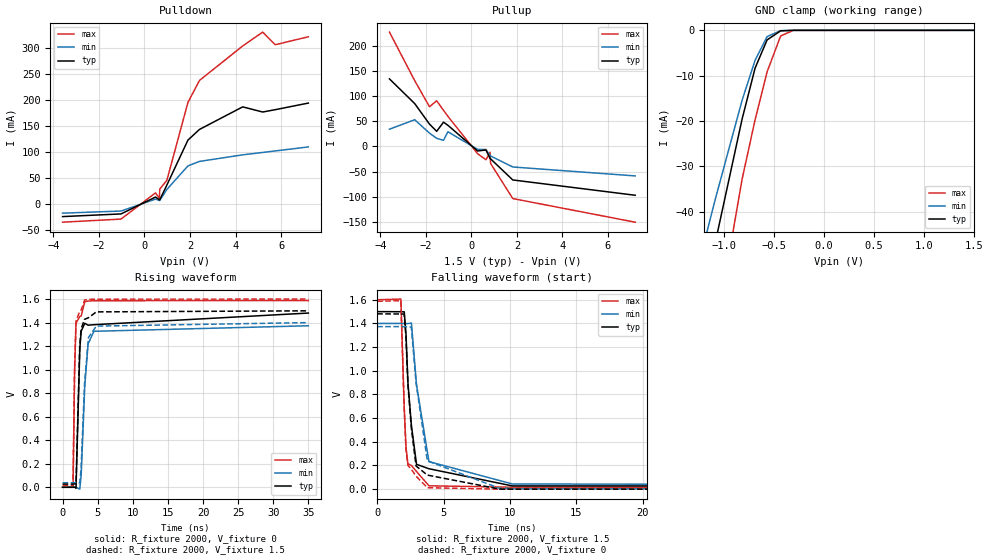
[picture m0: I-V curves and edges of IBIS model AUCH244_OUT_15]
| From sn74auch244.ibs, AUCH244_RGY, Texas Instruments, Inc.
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[Model]   AUCH244_OUT_15
Model_type  3-state
Enable   Active-Low
Vref =   0
Rref =   2000
Cref =   15p
Vmeas =   0.75
| variable   typ   min   max
C_comp   5.80pF   5.23pF   6.10pF
| C_pullup   5.20pF   0.65pF   12.77pF
| C_pulldown   6.55pF   5.62pF   10.14pF
| C_tri-state   5.80pF   5.23pF   6.10pF
[Temperature Range]   40   100   -40
| Ambient temperature   25   85   -40
[Voltage range]   1.5   1.4   1.6
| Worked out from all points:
|   slope of the pulldown table from 0 to 0.225 V, typ, clamps not added: 37.2 ohm
|   slope of the pullup table from 0 to 0.225 V, typ, clamps not added: 29.7 ohm
|   GND clamp passes 1 mA (typ) near -0.53 V on its own axis
|   rising waveform, R_fixture 2000, V_fixture 0: 20-80 % time 415ps typ, 649ps min, 258ps max; typ from 0 V to 1.48 V
|   falling waveform, R_fixture 2000, V_fixture 1.5: 20-80 % time 562ps typ, 892ps min, 311ps max; typ from 1.5 V to 0.027 V
|   rising waveform, R_fixture 2000, V_fixture 1.5: 20-80 % time 410ps typ, 643ps min, 254ps max; typ from 0.027 V to 1.5 V
|   falling waveform, R_fixture 2000, V_fixture 0: 20-80 % time 559ps typ, 887ps min, 309ps max; typ from 1.48 V to 0 V
[GND Clamp]
| AUCH244_OUT_15
|   Voltage   I(typ)   I(min)   I(max)
-3.6V     -322.8mA   -271.3mA   -392.8mA
-1.475V   -88.58mA   -71.53mA   -117.9mA
-1.34V    -73.9mA    -59.4mA    -100.2mA
-1.3V     -69.58mA   -55.84mA   -94.96mA
-1.135V   -51.89mA   -41.37mA   -73.3mA
-1.085V   -46.59mA   -37.07mA   -66.74mA
-820mV    -19.61mA   -15.46mA   -32.88mA
-690mV    -8.335mA   -6.603mA   -19.75mA
-570mV    -2.107mA   -1.377mA   -9.166mA
-435mV    -119.4uA   -67.95uA   -1.249mA
-310mV    -3.104uA   -3.773uA   -25uA
1.5V      550.3pA    10.34nA    544.8pA
[Pulldown]
| AUCH244_OUT_15
|   Voltage   I(typ)   I(min)   I(max)
-3.6V     -23.87mA   -17.26mA   -34.61mA
-1.03V    -18.71mA   -13.15mA   -28.63mA
485mV     13.68mA    9.737mA    21.72mA
660mV     8.179mA    6.953mA    10.96mA
670mV     8.319mA    7.1mA      28.79mA
985mV     36.88mA    28.41mA    46.12mA
1.91V     123.2mA    73.57mA    195.6mA
2.415V    143.6mA    82.17mA    237.7mA
4.315V    187mA      94.84mA    304mA
5.195V    177.1mA    99.4mA     330.7mA
5.745V    181.6mA    102.3mA    306.4mA
7.2V      194.3mA    110mA      321.7mA
[Pullup]
| AUCH244_OUT_15
|   Voltage   I(typ)   I(min)   I(max)
-3.6V     133.9mA    34.19mA    226.6mA
-2.49V    84.93mA    52.91mA    130.4mA
-1.84V    44.23mA    26.42mA    78.7mA
-1.525V   29.94mA    16.1mA     90.45mA
-1.225V   48.04mA    12.14mA    71.67mA
-1.03V    41.9mA     29.08mA    59.59mA
275mV     -9.031mA   -5.857mA   -14.38mA
640mV     -6.934mA   -6.165mA   -26.37mA
820mV     -23.65mA   -18mA      -11.49mA
845mV     -24.61mA   -18.86mA   -33.67mA
1.82V     -66.42mA   -40.7mA    -103.3mA
7.2V      -96.75mA   -58.41mA   -150.1mA
[Ramp]
| AUCH244_OUT_15
| variable   typ   min   max
dV/dt_r   0.90/4.22E-10   0.83/6.56E-10   0.96/2.59E-10
dV/dt_f   0.89/5.67E-10   0.82/8.95E-10   0.95/3.11E-10
R_load = 2000
[Rising Waveform]
| AUCH244_OUT_15
R_fixture =   2000
C_fixture =   0
L_fixture =   0
V_fixture =   0
V_fixture_min = 0
V_fixture_max = 0
|   Time   V(typ)   V(min)   V(max)
0s        9.799nV    37.56nV    981.3pV
1.495ns   8.668uV    -7.95uV    4.022mV
1.715ns   1.584mV    -21.38uV   990.6mV
1.915ns   -8.391mV   228.8uV    1.395V
2.455ns   1.179V     -15.98mV   1.453V
2.655ns   1.327V     108.2mV    1.457V
3.16ns    1.394V     858.1mV    1.577V
3.635ns   1.378V     1.218V     1.583V
4.46ns    1.382V     1.326V     1.586V
34.99ns   1.481V     1.373V     1.587V
[Falling Waveform]
| AUCH244_OUT_15
R_fixture =   2000
C_fixture =   0
L_fixture =   0
V_fixture =   1.5
V_fixture_min = 1.4
V_fixture_max = 1.6
|   Time   V(typ)   V(min)   V(max)
0s        1.5V       1.4V       1.6V
1.785ns   1.499V     1.4V       1.606V
2.04ns    1.498V     1.4V       686.1mV
2.175ns   1.302V     1.398V     348.3mV
2.32ns    896mV      1.399V     213.7mV
2.58ns    538.5mV    1.403V     199.7mV
2.965ns   209.8mV    881.4mV    149.2mV
3.9ns     172.5mV    232.9mV    28.58mV
10.18ns   27.54mV    43.93mV    16.5mV
34.99ns   27.21mV    38.76mV    16.42mV
[Rising Waveform]
| AUCH244_OUT_15
R_fixture =   2000
C_fixture =   0
L_fixture =   0
V_fixture =   1.5
V_fixture_min = 1.4
V_fixture_max = 1.6
|   Time   V(typ)   V(min)   V(max)
0s        27.17mV    38.75mV    16.4mV
1.485ns   27.18mV    38.74mV    17.04mV
1.72ns    28.78mV    38.73mV    1.033V
1.915ns   29.49mV    38.98mV    1.414V
2.445ns   1.201V     36.69mV    1.495V
2.64ns    1.346V     160.9mV    1.505V
3.13ns    1.428V     880.7mV    1.592V
3.685ns   1.441V     1.273V     1.597V
4.805ns   1.491V     1.37V      1.599V
34.99ns   1.5V       1.4V       1.6V
[Falling Waveform]
| AUCH244_OUT_15
R_fixture =   2000
C_fixture =   0
L_fixture =   0
V_fixture =   0
V_fixture_min = 0
V_fixture_max = 0
|   Time   V(typ)   V(min)   V(max)
0s        1.481V     1.373V     1.587V
1.785ns   1.48V      1.373V     1.592V
2.035ns   1.479V     1.372V     685.7mV
2.17ns    1.286V     1.371V     337.1mV
2.315ns   887.8mV    1.372V     200.6mV
2.575ns   515.4mV    1.369V     167.2mV
2.93ns    195.8mV    899.4mV    110mV
3.78ns    118.9mV    239.7mV    12.31mV
9.235ns   434.7uV    5.896mV    117.1uV
34.99ns   40.58uV    6.202uV    17.92uV
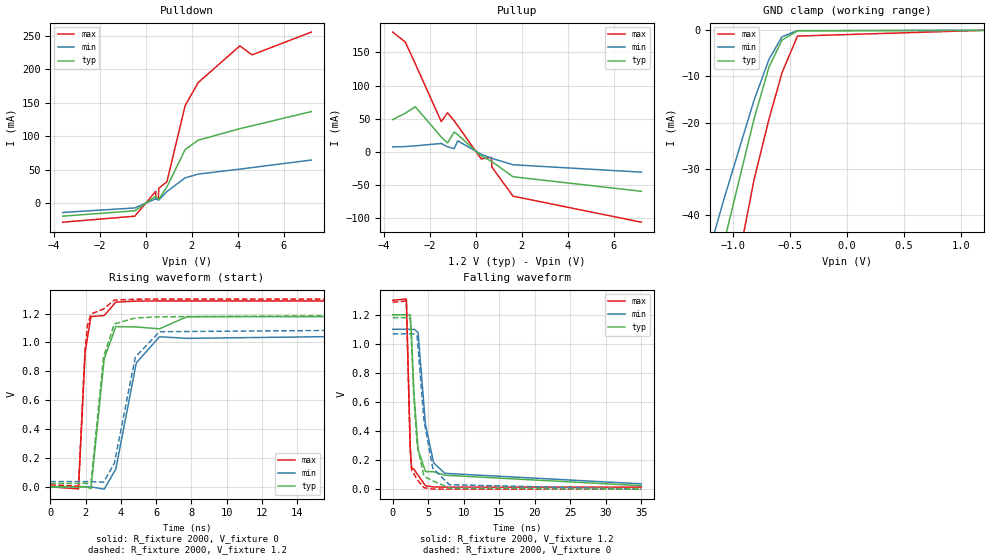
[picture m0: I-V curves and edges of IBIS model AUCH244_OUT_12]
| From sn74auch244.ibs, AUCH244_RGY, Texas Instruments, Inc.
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[Model]   AUCH244_OUT_12
Model_type  3-state
Enable   Active-Low
Vref =   0
Rref =   2000
Cref =   15p
Vmeas =   0.6
| variable   typ   min   max
C_comp   5.91pF   5.37pF   6.19pF
| C_pullup   5.14pF   0.31pF   10.09pF
| C_pulldown   6.52pF   5.74pF   7.72pF
| C_tri-state   5.91pF   5.37pF   6.19pF
[Temperature Range]   40   100   -40
| Ambient temperature   25   85   -40
[Voltage range]   1.2   1.1   1.3
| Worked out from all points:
|   slope of the pulldown table from 0 to 0.18 V, typ, clamps not added: 42.1 ohm
|   slope of the pullup table from 0 to 0.18 V, typ, clamps not added: 38.3 ohm
|   GND clamp passes 1 mA (typ) near -0.53 V on its own axis
|   rising waveform, R_fixture 2000, V_fixture 0: 20-80 % time 607ps typ, 1.03ns min, 332ps max; typ from 0 V to 1.18 V
|   falling waveform, R_fixture 2000, V_fixture 1.2: 20-80 % time 893ps typ, 1.4ns min, 432ps max; typ from 1.2 V to 0.024 V
|   rising waveform, R_fixture 2000, V_fixture 1.2: 20-80 % time 596ps typ, 1.03ns min, 326ps max; typ from 0.024 V to 1.2 V
|   falling waveform, R_fixture 2000, V_fixture 0: 20-80 % time 880ps typ, 1.33ns min, 425ps max; typ from 1.18 V to 0 V
[GND Clamp]
| AUCH244_OUT_12
|   Voltage   I(typ)   I(min)   I(max)
-3.6V     -322.8mA   -271.3mA   -392.8mA
-1.47V    -88.04mA   -71.07mA   -117.2mA
-1.425V   -83.13mA   -67.01mA   -111.4mA
-1.3V     -69.58mA   -55.84mA   -94.96mA
-1.26V    -65.26mA   -52.3mA    -89.71mA
-1.11V    -49.24mA   -39.21mA   -70.02mA
-1.075V   -45.54mA   -36.21mA   -65.43mA
-815mV    -19.13mA   -15.09mA   -32.31mA
-685mV    -7.974mA   -6.312mA   -19.28mA
-570mV    -2.107mA   -1.377mA   -9.166mA
-435mV    -119.4uA   -67.95uA   -1.249mA
1.2V      442.5pA    10.22nA    389.6pA
[Pulldown]
| AUCH244_OUT_12
|   Voltage   I(typ)   I(min)   I(max)
-3.6V     -19.18mA   -13.63mA   -28.17mA
-470mV    -11.13mA   -6.91mA    -19.23mA
440mV     10.48mA    6.706mA    17.92mA
445mV     10.59mA    6.769mA    6.318mA
560mV     5.857mA    4.698mA    8.209mA
570mV     5.97mA     4.786mA    22.41mA
925mV     24.38mA    17.54mA    32.09mA
1.72V     80.36mA    38.11mA    146mA
2.285V    94.25mA    43.63mA    180.3mA
4.095V    111.5mA    51.07mA    235.1mA
4.625V    115.8mA    53.41mA    221.7mA
7.2V      137mA      64.62mA    255.7mA
[Pullup]
| AUCH244_OUT_12
|   Voltage   I(typ)   I(min)   I(max)
-3.6V     48.8mA     7.73mA     180.5mA
-3.05V    58.5mA     8.2mA      165.4mA
-2.62V    68.11mA    9.305mA    132.9mA
-1.49V    22.6mA     12.87mA    45.69mA
-1.22V    13.65mA    7.955mA    59.11mA
-930mV    30.05mA    5.089mA    46.94mA
-775mV    26.1mA     16.83mA    39.5mA
245mV     -5.916mA   -3.381mA   -10.43mA
690mV     -14.05mA   -9.319mA   -7.997mA
705mV     -14.25mA   -9.473mA   -22.45mA
1.625V    -37.21mA   -19.16mA   -66.42mA
7.2V      -59.11mA   -30.28mA   -105.6mA
[Ramp]
| AUCH244_OUT_12
| variable   typ   min   max
dV/dt_r   0.72/6.09E-10   0.65/1.04E-09   0.78/3.37E-10
dV/dt_f   0.71/8.95E-10   0.64/1.40E-09   0.78/4.35E-10
R_load = 2000
[Rising Waveform]
| AUCH244_OUT_12
R_fixture =   2000
C_fixture =   0
L_fixture =   0
V_fixture =   0
V_fixture_min = 0
V_fixture_max = 0
|   Time   V(typ)   V(min)   V(max)
0s        9.189nV    39.93nV    791.2pV
1.6ns     -9.428uV   -3.122uV   -13.91mV
1.975ns   1.334mV    -22.29uV   931.3mV
2.305ns   -12.2mV    60.75uV    1.179V
3.055ns   886.6mV    -15.95mV   1.186V
3.715ns   1.109V     123.4mV    1.279V
4.875ns   1.107V     858.2mV    1.286V
6.19ns    1.094V     1.039V     1.287V
7.75ns    1.178V     1.028V     1.287V
34.99ns   1.18V      1.069V     1.287V
[Falling Waveform]
| AUCH244_OUT_12
R_fixture =   2000
C_fixture =   0
L_fixture =   0
V_fixture =   1.2
V_fixture_min = 1.1
V_fixture_max = 1.3
|   Time   V(typ)   V(min)   V(max)
0s        1.2V       1.1V       1.3V
1.92ns    1.2V       1.1V       1.308V
2.47ns    1.199V     1.1V       287.2mV
2.66ns    1.034V     1.098V     147.2mV
2.995ns   653.2mV    1.101V     136.9mV
3.575ns   269.8mV    1.078V     95.36mV
4.61ns    121.2mV    444.2mV    23.38mV
5.76ns    120mV      181.3mV    14.93mV
7.34ns    96.07mV    108.9mV    14.15mV
34.99ns   24.03mV    36.64mV    13.88mV
[Rising Waveform]
| AUCH244_OUT_12
R_fixture =   2000
C_fixture =   0
L_fixture =   0
V_fixture =   1.2
V_fixture_min = 1.1
V_fixture_max = 1.3
|   Time   V(typ)   V(min)   V(max)
0s        23.98mV    36.61mV    13.86mV
1.6ns     23.97mV    36.6mV     5.31mV
1.97ns    25.19mV    36.59mV    950.5mV
2.11ns    22.28mV    36.56mV    1.118V
2.305ns   26.37mV    36.68mV    1.197V
3.02ns    899.5mV    31.99mV    1.231V
3.63ns    1.128V     163.3mV    1.293V
4.82ns    1.169V     898.1mV    1.299V
6.185ns   1.177V     1.074V     1.3V
34.99ns   1.2V       1.1V       1.3V
[Falling Waveform]
| AUCH244_OUT_12
R_fixture =   2000
C_fixture =   0
L_fixture =   0
V_fixture =   0
V_fixture_min = 0
V_fixture_max = 0
|   Time   V(typ)   V(min)   V(max)
0s        1.18V      1.069V     1.287V
1.92ns    1.18V      1.069V     1.294V
2.46ns    1.176V     1.069V     275.6mV
2.65ns    1.013V     1.067V     134.2mV
2.965ns   640.6mV    1.069V     109.3mV
3.44ns    305.8mV    1.053V     65.29mV
4.4ns     88.28mV    473.4mV    9.989mV
5.64ns    57.55mV    144.3mV    929.8uV
7.97ns    7.606mV    30.8mV     202.3uV
34.99ns   50.29uV    16.34uV    18.98uV
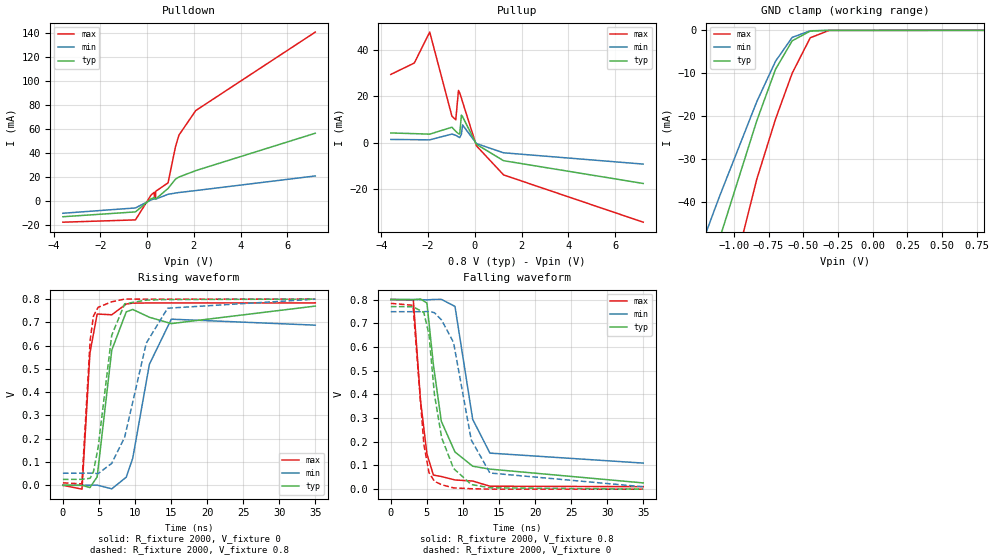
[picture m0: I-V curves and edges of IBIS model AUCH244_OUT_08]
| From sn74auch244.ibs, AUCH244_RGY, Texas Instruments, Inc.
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[Model]   AUCH244_OUT_08
Model_type  3-state
Enable   Active-Low
Vref =   0
Rref =   2000
Cref =   15p
Vmeas =   0.4
| variable   typ   min   max
C_comp   6.01pF   5.50pF   6.26pF
| C_pullup   6.18pF   1.68pF   8.54pF
| C_pulldown   6.67pF   6.06pF   7.13pF
| C_tri-state   6.01pF   5.50pF   6.26pF
[Temperature Range]   40   100   -40
| Ambient temperature   25   85   -40
[Voltage range]   0.8   0.8   0.8
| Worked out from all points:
|   slope of the pulldown table from 0 to 0.12 V, typ, clamps not added: 77.5 ohm
|   slope of the pullup table from 0 to 0.12 V, typ, clamps not added: 92.9 ohm
|   GND clamp passes 1 mA (typ) near -0.53 V on its own axis
|   rising waveform, R_fixture 2000, V_fixture 0: 20-80 % time 1.8ns typ, 2.48ns min, 963ps max; typ from 0 V to 0.77 V
|   falling waveform, R_fixture 2000, V_fixture 0.8: 20-80 % time 2.75ns typ, 2.16ns min, 1.41ns max; typ from 0.8 V to 0.026 V
|   rising waveform, R_fixture 2000, V_fixture 0.8: 20-80 % time 1.83ns typ, 3.55ns min, 910ps max; typ from 0.025 V to 0.8 V
|   falling waveform, R_fixture 2000, V_fixture 0: 20-80 % time 2.26ns typ, 2.82ns min, 1.27ns max; typ from 0.77 V to 0 V
[GND Clamp]
| AUCH244_OUT_08
|   Voltage   I(typ)   I(min)   I(max)
-3.6V     -322.8mA   -271.3mA   -392.8mA
-1.495V   -90.76mA   -73.33mA   -120.5mA
-1.455V   -86.4mA    -69.72mA   -115.3mA
-1.31V    -70.66mA   -56.73mA   -96.27mA
-1.14V    -52.42mA   -41.8mA    -73.96mA
-1.1V     -48.18mA   -38.36mA   -68.71mA
-835mV    -21.05mA   -16.6mA    -34.66mA
-700mV    -9.079mA   -7.199mA   -20.67mA
-580mV    -2.442mA   -1.648mA   -9.983mA
-450mV    -176.5uA   -96.05uA   -1.735mA
-315mV    -3.617uA   -4.294uA   -30.24uA
800mV     320.2pA    582.3pA    244.4pA
[Pulldown]
| AUCH244_OUT_08
|   Voltage   I(typ)   I(min)   I(max)
-3.6V     -12.84mA   -9.953mA   -17.38mA
-495mV    -8.803mA   -5.523mA   -15.47mA
175mV     2.059mA    1.185mA    5.31mA
310mV     3.174mA    2.053mA    7.502mA
315mV     3.217mA    2.087mA    2.47mA
365mV     1.856mA    1.796mA    2.807mA
370mV     1.894mA    1.829mA    8.27mA
900mV     10.72mA    5.829mA    15.4mA
1.215V    18.4mA     6.852mA    45.18mA
1.365V    20.2mA     7.318mA    55.07mA
2.085V    25.54mA    8.939mA    75.52mA
7.2V      56.65mA    21.1mA     140.8mA
[Pullup]
| AUCH244_OUT_08
|   Voltage   I(typ)   I(min)   I(max)
-3.6V     4.13mA     1.333mA    29.34mA
-2.595V   3.829mA    1.231mA    34.24mA
-1.935V   3.609mA    1.155mA    47.57mA
-985mV    6.593mA    3.652mA    11.35mA
-820mV    4.807mA    3.079mA    9.795mA
-705mV    3.788mA    2.41mA     22.46mA
-650mV    3.702mA    2.149mA    21.3mA
-580mV    11.83mA    3.56mA     19.16mA
-530mV    11.15mA    7.583mA    17.47mA
65mV      -779.5uA   -459.6uA   -1.427mA
1.225V    -7.82mA    -4.418mA   -13.94mA
7.2V      -17.63mA   -9.285mA   -34.31mA
[Ramp]
| AUCH244_OUT_08
| variable   typ   min   max
dV/dt_r   0.47/1.82E-09   0.46/2.98E-09   0.48/9.73E-10
dV/dt_f   0.47/2.75E-09   0.42/2.17E-09   0.48/1.41E-09
R_load = 2000
[Rising Waveform]
| AUCH244_OUT_08
R_fixture =   2000
C_fixture =   0
L_fixture =   0
V_fixture =   0
V_fixture_min = 0
V_fixture_max = 0
|   Time   V(typ)   V(min)   V(max)
0s        11.33nV    65.3nV     597.2pV
2.65ns    167.1uV    -63.08uV   -16.57mV
3.75ns    -9.745mV   362uV      568.9mV
4.75ns    36.42mV    984.1uV    735.8mV
6.775ns   580.6mV    -15.05mV   732.6mV
8.78ns    745.1mV    34.86mV    778.7mV
9.68ns    755.6mV    115.9mV    782.6mV
11.99ns   721.9mV    519.9mV    783.4mV
15.03ns   694.7mV    713.7mV    783.6mV
34.99ns   769.9mV    688mV      783.7mV
[Falling Waveform]
| AUCH244_OUT_08
R_fixture =   2000
C_fixture =   0
L_fixture =   0
V_fixture =   0.8
V_fixture_min = 0.8
V_fixture_max = 0.8
|   Time   V(typ)   V(min)   V(max)
0s        800mV      800mV      800mV
3.12ns    799.3mV    800.1mV    797.8mV
4.115ns   801.9mV    799.5mV    374.6mV
5.005ns   785.3mV    798.4mV    149mV
5.905ns   524.5mV    800.3mV    59.44mV
7ns       286.6mV    800.8mV    53.43mV
8.895ns   156.9mV    770.9mV    38.81mV
11.35ns   96.89mV    294.6mV    34.42mV
13.74ns   84.61mV    152.1mV    12.44mV
34.99ns   26.39mV    110mV      10.63mV
[Rising Waveform]
| AUCH244_OUT_08
R_fixture =   2000
C_fixture =   0
L_fixture =   0
V_fixture =   0.8
V_fixture_min = 0.8
V_fixture_max = 0.8
|   Time   V(typ)   V(min)   V(max)
0s        25.46mV    51.93mV    10.6mV
2.625ns   25.59mV    51.91mV    6.312mV
3.785ns   30.25mV    52.29mV    625.1mV
4.235ns   58.44mV    52.06mV    726.9mV
4.88ns    162.4mV    50.13mV    764.5mV
6.765ns   644.3mV    94.19mV    788.3mV
8.565ns   779.7mV    206.7mV    800.1mV
11.55ns   795.7mV    610.3mV    799.7mV
14.52ns   798mV      760.8mV    799.8mV
34.99ns   799.9mV    799.5mV    800mV
[Falling Waveform]
| AUCH244_OUT_08
R_fixture =   2000
C_fixture =   0
L_fixture =   0
V_fixture =   0
V_fixture_min = 0
V_fixture_max = 0
|   Time   V(typ)   V(min)   V(max)
0s        770mV      748.6mV    783.8mV
3.075ns   769.6mV    748.6mV    775.6mV
4.58ns    745.2mV    748.5mV    189.2mV
5.29ns    652.3mV    750.1mV    69.98mV
6.04ns    401.2mV    744.4mV    33.4mV
7.05ns    217mV      713mV      18.72mV
8.695ns   87.41mV    619.1mV    5.311mV
11.15ns   19.67mV    207.8mV    1.905mV
13.74ns   5.804mV    68.17mV    209.2uV
34.99ns   148.5uV    10.18mV    30.7uV
